One B-rep face of a CAD part: STEP entity #211.
In plain terms, the planar face has unit normal (1, 0, 0).
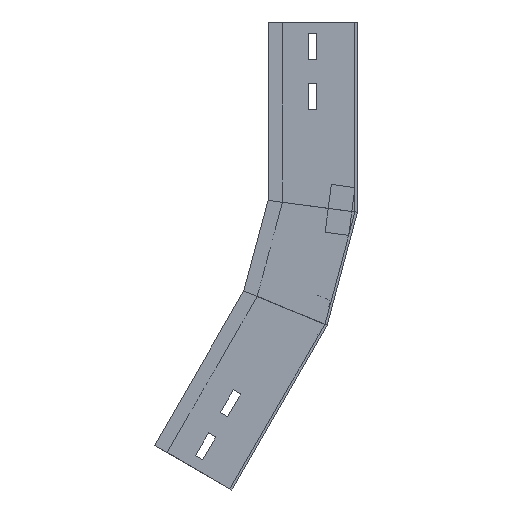
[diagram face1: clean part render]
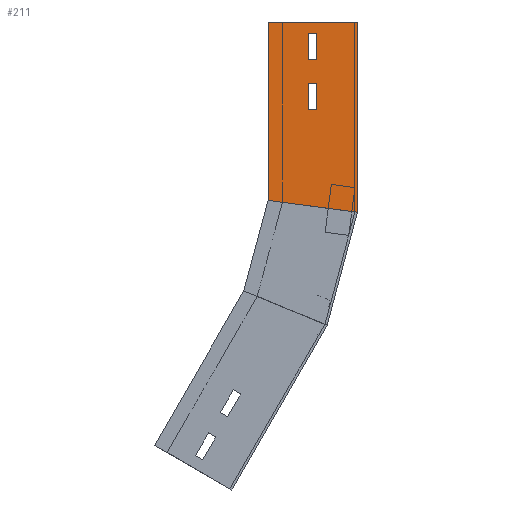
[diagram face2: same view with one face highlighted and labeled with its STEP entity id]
Its self-contained STEP definition (entity closure, numbers rounded to 3 decimals):
#11 = CARTESIAN_POINT ( 'NONE',  ( 0., 90.394, -217.151 ) ) ;
#25 = VERTEX_POINT ( 'NONE', #294 ) ;
#28 = CARTESIAN_POINT ( 'NONE',  ( 0., 124.881, -344.885 ) ) ;
#35 = CARTESIAN_POINT ( 'NONE',  ( 0., 25.442, -254.651 ) ) ;
#42 = CARTESIAN_POINT ( 'NONE',  ( 0., 104.046, -308.798 ) ) ;
#56 = LINE ( 'NONE', #1199, #935 ) ;
#71 = CARTESIAN_POINT ( 'NONE',  ( 0., 170.244, -355.455 ) ) ;
#101 = LINE ( 'NONE', #326, #1150 ) ;
#102 = DIRECTION ( 'NONE',  ( -1., 0., 0. ) ) ;
#103 = ORIENTED_EDGE ( 'NONE', *, *, #1028, .T. ) ;
#130 = VECTOR ( 'NONE', #1218, 1000. ) ;
#132 = DIRECTION ( 'NONE',  ( 0., -0.866, -0.5 ) ) ;
#146 = LINE ( 'NONE', #1426, #308 ) ;
#155 = VERTEX_POINT ( 'NONE', #1123 ) ;
#190 = ORIENTED_EDGE ( 'NONE', *, *, #427, .F. ) ;
#211 = ADVANCED_FACE ( 'NONE', ( #1136, #327, #781 ), #763, .F. ) ;
#215 = DIRECTION ( 'NONE',  ( 0., 0.866, 0.5 ) ) ;
#226 = CARTESIAN_POINT ( 'NONE',  ( 0., 105.292, -392.955 ) ) ;
#260 = ORIENTED_EDGE ( 'NONE', *, *, #793, .F. ) ;
#262 = EDGE_CURVE ( 'NONE', #928, #709, #795, .T. ) ;
#271 = LINE ( 'NONE', #42, #860 ) ;
#282 = CARTESIAN_POINT ( 'NONE',  ( 0., 135.881, -363.937 ) ) ;
#284 = VECTOR ( 'NONE', #953, 1000. ) ;
#294 = CARTESIAN_POINT ( 'NONE',  ( 0., 97.984, -312.298 ) ) ;
#297 = CARTESIAN_POINT ( 'NONE',  ( 0., 95.331, -225.702 ) ) ;
#299 = CARTESIAN_POINT ( 'NONE',  ( 0., 115.046, -327.85 ) ) ;
#308 = VECTOR ( 'NONE', #1101, 1000. ) ;
#326 = CARTESIAN_POINT ( 'NONE',  ( 0., 129.819, -367.437 ) ) ;
#327 = FACE_BOUND ( 'NONE', #621, .T. ) ;
#365 = LINE ( 'NONE', #28, #821 ) ;
#389 = EDGE_CURVE ( 'NONE', #437, #1253, #365, .T. ) ;
#392 = DIRECTION ( 'NONE',  ( 0., 0.5, -0.866 ) ) ;
#397 = DIRECTION ( 'NONE',  ( 0., -0.5, 0.866 ) ) ;
#405 = LINE ( 'NONE', #282, #716 ) ;
#412 = EDGE_LOOP ( 'NONE', ( #103, #596, #741, #450 ) ) ;
#427 = EDGE_CURVE ( 'NONE', #732, #437, #405, .T. ) ;
#437 = VERTEX_POINT ( 'NONE', #846 ) ;
#443 = EDGE_CURVE ( 'NONE', #709, #1440, #1451, .T. ) ;
#450 = ORIENTED_EDGE ( 'NONE', *, *, #715, .F. ) ;
#481 = CARTESIAN_POINT ( 'NONE',  ( 0., 118.819, -348.385 ) ) ;
#494 = DIRECTION ( 'NONE',  ( 0., -0.866, -0.5 ) ) ;
#497 = EDGE_CURVE ( 'NONE', #729, #732, #146, .T. ) ;
#513 = EDGE_CURVE ( 'NONE', #818, #155, #871, .T. ) ;
#551 = DIRECTION ( 'NONE',  ( 0., 0., 1. ) ) ;
#563 = EDGE_CURVE ( 'NONE', #1253, #729, #101, .T. ) ;
#596 = ORIENTED_EDGE ( 'NONE', *, *, #262, .T. ) ;
#621 = EDGE_LOOP ( 'NONE', ( #1482, #1447, #904, #260 ) ) ;
#701 = LINE ( 'NONE', #11, #933 ) ;
#709 = VERTEX_POINT ( 'NONE', #226 ) ;
#715 = EDGE_CURVE ( 'NONE', #937, #1440, #701, .T. ) ;
#716 = VECTOR ( 'NONE', #397, 1000. ) ;
#729 = VERTEX_POINT ( 'NONE', #1033 ) ;
#732 = VERTEX_POINT ( 'NONE', #931 ) ;
#741 = ORIENTED_EDGE ( 'NONE', *, *, #443, .T. ) ;
#743 = CARTESIAN_POINT ( 'NONE',  ( 0., 25.442, -254.651 ) ) ;
#763 = PLANE ( 'NONE',  #1141 ) ;
#775 = LINE ( 'NONE', #1350, #130 ) ;
#781 = FACE_OUTER_BOUND ( 'NONE', #412, .T. ) ;
#788 = CARTESIAN_POINT ( 'NONE',  ( 0., 25.442, -254.651 ) ) ;
#793 = EDGE_CURVE ( 'NONE', #155, #25, #271, .T. ) ;
#795 = LINE ( 'NONE', #35, #1004 ) ;
#814 = DIRECTION ( 'NONE',  ( 0., 0.5, -0.866 ) ) ;
#818 = VERTEX_POINT ( 'NONE', #987 ) ;
#821 = VECTOR ( 'NONE', #132, 1000. ) ;
#846 = CARTESIAN_POINT ( 'NONE',  ( 0., 124.881, -344.885 ) ) ;
#860 = VECTOR ( 'NONE', #494, 1000. ) ;
#871 = LINE ( 'NONE', #299, #284 ) ;
#875 = VECTOR ( 'NONE', #1096, 1000. ) ;
#904 = ORIENTED_EDGE ( 'NONE', *, *, #1241, .F. ) ;
#928 = VERTEX_POINT ( 'NONE', #743 ) ;
#931 = CARTESIAN_POINT ( 'NONE',  ( 0., 135.881, -363.937 ) ) ;
#933 = VECTOR ( 'NONE', #1140, 1000. ) ;
#935 = VECTOR ( 'NONE', #392, 1000. ) ;
#937 = VERTEX_POINT ( 'NONE', #297 ) ;
#953 = DIRECTION ( 'NONE',  ( 0., -0.5, 0.866 ) ) ;
#987 = CARTESIAN_POINT ( 'NONE',  ( 0., 115.046, -327.85 ) ) ;
#1004 = VECTOR ( 'NONE', #814, 1000. ) ;
#1028 = EDGE_CURVE ( 'NONE', #937, #928, #775, .T. ) ;
#1033 = CARTESIAN_POINT ( 'NONE',  ( 0., 129.819, -367.437 ) ) ;
#1096 = DIRECTION ( 'NONE',  ( 0., 0.866, 0.5 ) ) ;
#1101 = DIRECTION ( 'NONE',  ( 0., 0.866, 0.5 ) ) ;
#1123 = CARTESIAN_POINT ( 'NONE',  ( 0., 104.046, -308.798 ) ) ;
#1136 = FACE_BOUND ( 'NONE', #1157, .T. ) ;
#1138 = LINE ( 'NONE', #1390, #1446 ) ;
#1140 = DIRECTION ( 'NONE',  ( 0., 0.5, -0.866 ) ) ;
#1141 = AXIS2_PLACEMENT_3D ( 'NONE', #788, #102, #551 ) ;
#1150 = VECTOR ( 'NONE', #1257, 1000. ) ;
#1157 = EDGE_LOOP ( 'NONE', ( #190, #1306, #1389, #1483 ) ) ;
#1199 = CARTESIAN_POINT ( 'NONE',  ( 0., 108.984, -331.35 ) ) ;
#1201 = VERTEX_POINT ( 'NONE', #1263 ) ;
#1213 = CARTESIAN_POINT ( 'NONE',  ( 0., 105.292, -392.955 ) ) ;
#1218 = DIRECTION ( 'NONE',  ( 0., -0.924, -0.383 ) ) ;
#1241 = EDGE_CURVE ( 'NONE', #25, #1201, #56, .T. ) ;
#1253 = VERTEX_POINT ( 'NONE', #481 ) ;
#1257 = DIRECTION ( 'NONE',  ( 0., 0.5, -0.866 ) ) ;
#1263 = CARTESIAN_POINT ( 'NONE',  ( 0., 108.984, -331.35 ) ) ;
#1306 = ORIENTED_EDGE ( 'NONE', *, *, #497, .F. ) ;
#1350 = CARTESIAN_POINT ( 'NONE',  ( 0., 37.296, -249.74 ) ) ;
#1389 = ORIENTED_EDGE ( 'NONE', *, *, #563, .F. ) ;
#1390 = CARTESIAN_POINT ( 'NONE',  ( 0., 115.046, -327.85 ) ) ;
#1426 = CARTESIAN_POINT ( 'NONE',  ( 0., 135.881, -363.937 ) ) ;
#1440 = VERTEX_POINT ( 'NONE', #71 ) ;
#1446 = VECTOR ( 'NONE', #215, 1000. ) ;
#1447 = ORIENTED_EDGE ( 'NONE', *, *, #1481, .F. ) ;
#1451 = LINE ( 'NONE', #1213, #875 ) ;
#1481 = EDGE_CURVE ( 'NONE', #1201, #818, #1138, .T. ) ;
#1482 = ORIENTED_EDGE ( 'NONE', *, *, #513, .F. ) ;
#1483 = ORIENTED_EDGE ( 'NONE', *, *, #389, .F. ) ;
